VERSION 5.7 ;
  NOWIREEXTENSIONATPIN ON ;
  DIVIDERCHAR "/" ;
  BUSBITCHARS "[]" ;
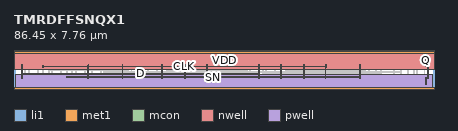
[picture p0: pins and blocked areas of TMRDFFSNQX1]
MACRO TMRDFFSNQX1
  CLASS CORE ;
  FOREIGN TMRDFFSNQX1 ;
  ORIGIN 0.000 0.000 ;
  SIZE 86.450 BY 7.760 ;
  SYMMETRY X Y ;
  SITE unitrh ;
  PIN Q
    DIRECTION OUTPUT ;
    USE SIGNAL ;
    ANTENNADIFFAREA 0.771900 ;
    PORT
      LAYER li1 ;
        RECT 84.770 4.845 84.940 7.200 ;
        RECT 84.770 4.675 85.305 4.845 ;
        RECT 85.135 2.345 85.305 4.675 ;
        RECT 84.765 2.175 85.305 2.345 ;
        RECT 84.765 1.020 84.935 2.175 ;
    END
  END Q
  PIN D
    DIRECTION INPUT ;
    USE SIGNAL ;
    ANTENNAGATEAREA 3.099750 ;
    PORT
      LAYER met1 ;
        RECT 1.485 3.225 1.715 3.255 ;
        RECT 25.905 3.225 26.135 3.255 ;
        RECT 50.325 3.225 50.555 3.255 ;
        RECT 1.455 3.055 50.585 3.225 ;
        RECT 1.485 3.025 1.715 3.055 ;
        RECT 25.905 3.025 26.135 3.055 ;
        RECT 50.325 3.025 50.555 3.055 ;
    END
    PORT
      LAYER li1 ;
        RECT 50.355 2.095 50.525 5.045 ;
      LAYER mcon ;
        RECT 50.355 3.055 50.525 3.225 ;
    END
    PORT
      LAYER li1 ;
        RECT 1.515 2.095 1.685 5.045 ;
      LAYER mcon ;
        RECT 1.515 3.055 1.685 3.225 ;
    END
  END D
  PIN CLK
    DIRECTION INPUT ;
    USE SIGNAL ;
    ANTENNAGATEAREA 6.126300 ;
    PORT
      LAYER met1 ;
        RECT 5.925 4.705 6.155 4.735 ;
        RECT 15.175 4.705 15.405 4.735 ;
        RECT 30.345 4.705 30.575 4.735 ;
        RECT 39.595 4.705 39.825 4.735 ;
        RECT 54.765 4.705 54.995 4.735 ;
        RECT 64.015 4.705 64.245 4.735 ;
        RECT 5.895 4.535 64.275 4.705 ;
        RECT 5.925 4.505 6.155 4.535 ;
        RECT 15.175 4.505 15.405 4.535 ;
        RECT 30.345 4.505 30.575 4.535 ;
        RECT 39.595 4.505 39.825 4.535 ;
        RECT 54.765 4.505 54.995 4.535 ;
        RECT 64.015 4.505 64.245 4.535 ;
    END
    PORT
      LAYER li1 ;
        RECT 15.235 4.890 15.405 5.045 ;
        RECT 15.205 4.715 15.405 4.890 ;
        RECT 15.205 2.095 15.375 4.715 ;
      LAYER mcon ;
        RECT 15.205 4.535 15.375 4.705 ;
    END
    PORT
      LAYER li1 ;
        RECT 30.375 2.095 30.545 5.045 ;
      LAYER mcon ;
        RECT 30.375 4.535 30.545 4.705 ;
    END
    PORT
      LAYER li1 ;
        RECT 39.655 4.890 39.825 5.045 ;
        RECT 39.625 4.715 39.825 4.890 ;
        RECT 39.625 2.095 39.795 4.715 ;
      LAYER mcon ;
        RECT 39.625 4.535 39.795 4.705 ;
    END
    PORT
      LAYER li1 ;
        RECT 54.795 2.095 54.965 5.045 ;
      LAYER mcon ;
        RECT 54.795 4.535 54.965 4.705 ;
    END
    PORT
      LAYER li1 ;
        RECT 64.075 4.890 64.245 5.045 ;
        RECT 64.045 4.715 64.245 4.890 ;
        RECT 64.045 2.095 64.215 4.715 ;
      LAYER mcon ;
        RECT 64.045 4.535 64.215 4.705 ;
    END
  END CLK
  PIN SN
    DIRECTION INPUT ;
    USE SIGNAL ;
    ANTENNAGATEAREA 6.089100 ;
    PORT
      LAYER met1 ;
        RECT 10.735 2.485 10.965 2.515 ;
        RECT 22.205 2.485 22.435 2.515 ;
        RECT 35.155 2.485 35.385 2.515 ;
        RECT 46.625 2.485 46.855 2.515 ;
        RECT 59.575 2.485 59.805 2.515 ;
        RECT 71.045 2.485 71.275 2.515 ;
        RECT 10.705 2.315 71.305 2.485 ;
        RECT 10.735 2.285 10.965 2.315 ;
        RECT 22.205 2.285 22.435 2.315 ;
        RECT 35.155 2.285 35.385 2.315 ;
        RECT 46.625 2.285 46.855 2.315 ;
        RECT 59.575 2.285 59.805 2.315 ;
        RECT 71.045 2.285 71.275 2.315 ;
    END
    PORT
      LAYER li1 ;
        RECT 22.235 2.095 22.405 5.045 ;
      LAYER mcon ;
        RECT 22.235 2.315 22.405 2.485 ;
    END
    PORT
      LAYER li1 ;
        RECT 35.185 2.095 35.355 5.045 ;
      LAYER mcon ;
        RECT 35.185 2.315 35.355 2.485 ;
    END
    PORT
      LAYER li1 ;
        RECT 59.605 2.095 59.775 5.045 ;
      LAYER mcon ;
        RECT 59.605 2.315 59.775 2.485 ;
    END
    PORT
      LAYER li1 ;
        RECT 71.075 2.095 71.245 5.045 ;
      LAYER mcon ;
        RECT 71.075 2.315 71.245 2.485 ;
    END
  END SN
  PIN VDD
    DIRECTION INOUT ;
    USE POWER ;
    SHAPE ABUTMENT ;
    PORT
      LAYER nwell ;
        RECT 0.000 4.110 86.450 7.940 ;
      LAYER met1 ;
        RECT 0.000 7.410 86.450 7.760 ;
    END
  END VDD
  PIN GND
    DIRECTION INOUT ;
    USE GROUND ;
    SHAPE ABUTMENT ;
    PORT
      LAYER pwell ;
        RECT 0.320 0.000 86.130 2.900 ;
      LAYER met1 ;
        RECT 0.000 0.000 86.450 0.350 ;
    END
  END GND
  OBS
      LAYER li1 ;
        RECT 0.000 7.410 86.450 7.760 ;
        RECT 0.320 4.290 0.660 7.410 ;
        RECT 1.195 5.315 1.365 7.410 ;
        RECT 1.635 5.465 1.805 7.200 ;
        RECT 2.075 5.735 2.245 7.410 ;
        RECT 2.515 5.465 2.685 7.200 ;
        RECT 2.955 5.735 3.125 7.410 ;
        RECT 1.635 5.295 3.165 5.465 ;
        RECT 2.285 4.890 2.455 5.045 ;
        RECT 2.255 4.715 2.455 4.890 ;
        RECT 0.320 0.350 0.660 2.900 ;
        RECT 2.255 2.095 2.425 4.715 ;
        RECT 1.100 1.845 1.270 1.925 ;
        RECT 2.070 1.845 2.240 1.925 ;
        RECT 2.995 1.920 3.165 5.295 ;
        RECT 3.650 4.290 3.990 7.410 ;
        RECT 4.825 5.395 4.995 7.410 ;
        RECT 5.265 5.420 5.435 7.200 ;
        RECT 5.705 5.735 5.875 7.410 ;
        RECT 6.145 5.420 6.315 7.200 ;
        RECT 6.585 5.735 6.755 7.410 ;
        RECT 7.025 5.420 7.195 7.200 ;
        RECT 7.465 5.735 7.635 7.410 ;
        RECT 5.265 5.250 7.975 5.420 ;
        RECT 1.100 1.675 2.240 1.845 ;
        RECT 1.100 0.545 1.270 1.675 ;
        RECT 1.585 0.350 1.755 1.300 ;
        RECT 2.070 0.795 2.240 1.675 ;
        RECT 2.555 1.750 3.165 1.920 ;
        RECT 2.555 1.015 2.725 1.750 ;
        RECT 3.040 0.795 3.210 1.565 ;
        RECT 2.070 0.625 3.210 0.795 ;
        RECT 2.070 0.545 2.240 0.625 ;
        RECT 3.040 0.545 3.210 0.625 ;
        RECT 3.650 0.350 3.990 2.900 ;
        RECT 4.845 2.095 5.015 5.045 ;
        RECT 5.955 2.095 6.125 5.045 ;
        RECT 7.065 2.095 7.235 5.045 ;
        RECT 7.805 4.415 7.975 5.250 ;
        RECT 7.800 4.085 7.975 4.415 ;
        RECT 8.460 4.290 8.800 7.410 ;
        RECT 9.635 5.395 9.805 7.410 ;
        RECT 10.075 5.420 10.245 7.200 ;
        RECT 10.515 5.735 10.685 7.410 ;
        RECT 10.955 5.420 11.125 7.200 ;
        RECT 11.395 5.735 11.565 7.410 ;
        RECT 11.835 5.420 12.005 7.200 ;
        RECT 12.275 5.735 12.445 7.410 ;
        RECT 10.075 5.250 12.785 5.420 ;
        RECT 4.325 1.855 4.495 1.935 ;
        RECT 5.295 1.855 5.465 1.935 ;
        RECT 6.265 1.855 6.435 1.935 ;
        RECT 4.325 1.685 6.435 1.855 ;
        RECT 4.325 0.555 4.495 1.685 ;
        RECT 4.810 0.350 4.980 1.310 ;
        RECT 5.295 0.805 5.465 1.685 ;
        RECT 6.265 1.605 6.435 1.685 ;
        RECT 5.785 1.260 5.955 1.340 ;
        RECT 6.835 1.260 7.005 1.935 ;
        RECT 7.805 1.930 7.975 4.085 ;
        RECT 5.785 1.090 7.005 1.260 ;
        RECT 5.785 1.010 5.955 1.090 ;
        RECT 6.265 0.805 6.435 0.885 ;
        RECT 5.295 0.635 6.435 0.805 ;
        RECT 5.295 0.555 5.465 0.635 ;
        RECT 6.265 0.555 6.435 0.635 ;
        RECT 6.835 0.805 7.005 1.090 ;
        RECT 7.320 1.760 7.975 1.930 ;
        RECT 7.320 1.025 7.490 1.760 ;
        RECT 7.805 0.805 7.975 1.575 ;
        RECT 6.835 0.635 7.975 0.805 ;
        RECT 6.835 0.555 7.005 0.635 ;
        RECT 7.805 0.555 7.975 0.635 ;
        RECT 8.460 0.350 8.800 2.900 ;
        RECT 9.655 2.095 9.825 5.045 ;
        RECT 10.765 2.095 10.935 5.045 ;
        RECT 11.875 2.095 12.045 5.045 ;
        RECT 9.135 1.855 9.305 1.935 ;
        RECT 10.105 1.855 10.275 1.935 ;
        RECT 11.075 1.855 11.245 1.935 ;
        RECT 9.135 1.685 11.245 1.855 ;
        RECT 9.135 0.555 9.305 1.685 ;
        RECT 9.620 0.350 9.790 1.310 ;
        RECT 10.105 0.805 10.275 1.685 ;
        RECT 11.075 1.605 11.245 1.685 ;
        RECT 10.595 1.260 10.765 1.340 ;
        RECT 11.645 1.260 11.815 1.935 ;
        RECT 12.615 1.930 12.785 5.250 ;
        RECT 13.270 4.290 13.610 7.410 ;
        RECT 14.145 5.315 14.315 7.410 ;
        RECT 14.585 5.465 14.755 7.200 ;
        RECT 15.025 5.735 15.195 7.410 ;
        RECT 15.465 5.465 15.635 7.200 ;
        RECT 15.905 5.735 16.075 7.410 ;
        RECT 14.585 5.295 16.115 5.465 ;
        RECT 10.595 1.090 11.815 1.260 ;
        RECT 10.595 1.010 10.765 1.090 ;
        RECT 11.075 0.805 11.245 0.885 ;
        RECT 10.105 0.635 11.245 0.805 ;
        RECT 10.105 0.555 10.275 0.635 ;
        RECT 11.075 0.555 11.245 0.635 ;
        RECT 11.645 0.805 11.815 1.090 ;
        RECT 12.130 1.760 12.785 1.930 ;
        RECT 12.130 1.025 12.300 1.760 ;
        RECT 12.615 0.805 12.785 1.575 ;
        RECT 11.645 0.635 12.785 0.805 ;
        RECT 11.645 0.555 11.815 0.635 ;
        RECT 12.615 0.555 12.785 0.635 ;
        RECT 13.270 0.350 13.610 2.900 ;
        RECT 14.465 2.095 14.635 5.045 ;
        RECT 14.050 1.845 14.220 1.925 ;
        RECT 15.020 1.845 15.190 1.925 ;
        RECT 15.945 1.920 16.115 5.295 ;
        RECT 16.600 4.290 16.940 7.410 ;
        RECT 17.475 5.315 17.645 7.410 ;
        RECT 17.915 5.465 18.085 7.200 ;
        RECT 18.355 5.735 18.525 7.410 ;
        RECT 18.795 5.465 18.965 7.200 ;
        RECT 19.235 5.735 19.405 7.410 ;
        RECT 17.915 5.295 19.445 5.465 ;
        RECT 14.050 1.675 15.190 1.845 ;
        RECT 14.050 0.545 14.220 1.675 ;
        RECT 14.535 0.350 14.705 1.300 ;
        RECT 15.020 0.795 15.190 1.675 ;
        RECT 15.505 1.750 16.115 1.920 ;
        RECT 15.505 1.015 15.675 1.750 ;
        RECT 15.990 0.795 16.160 1.565 ;
        RECT 15.020 0.625 16.160 0.795 ;
        RECT 15.020 0.545 15.190 0.625 ;
        RECT 15.990 0.545 16.160 0.625 ;
        RECT 16.600 0.350 16.940 2.900 ;
        RECT 17.795 2.095 17.965 5.045 ;
        RECT 18.565 4.890 18.735 5.045 ;
        RECT 18.535 4.715 18.735 4.890 ;
        RECT 18.535 2.095 18.705 4.715 ;
        RECT 17.380 1.845 17.550 1.925 ;
        RECT 18.350 1.845 18.520 1.925 ;
        RECT 19.275 1.920 19.445 5.295 ;
        RECT 19.930 4.290 20.270 7.410 ;
        RECT 21.105 5.395 21.275 7.410 ;
        RECT 21.545 5.420 21.715 7.200 ;
        RECT 21.985 5.735 22.155 7.410 ;
        RECT 22.425 5.420 22.595 7.200 ;
        RECT 22.865 5.735 23.035 7.410 ;
        RECT 23.305 5.420 23.475 7.200 ;
        RECT 23.745 5.735 23.915 7.410 ;
        RECT 21.545 5.250 24.255 5.420 ;
        RECT 17.380 1.675 18.520 1.845 ;
        RECT 17.380 0.545 17.550 1.675 ;
        RECT 17.865 0.350 18.035 1.300 ;
        RECT 18.350 0.795 18.520 1.675 ;
        RECT 18.835 1.750 19.445 1.920 ;
        RECT 18.835 1.015 19.005 1.750 ;
        RECT 19.320 0.795 19.490 1.565 ;
        RECT 18.350 0.625 19.490 0.795 ;
        RECT 18.350 0.545 18.520 0.625 ;
        RECT 19.320 0.545 19.490 0.625 ;
        RECT 19.930 0.350 20.270 2.900 ;
        RECT 21.125 2.095 21.295 5.045 ;
        RECT 23.345 2.095 23.515 5.045 ;
        RECT 20.605 1.855 20.775 1.935 ;
        RECT 21.575 1.855 21.745 1.935 ;
        RECT 22.545 1.855 22.715 1.935 ;
        RECT 20.605 1.685 22.715 1.855 ;
        RECT 20.605 0.555 20.775 1.685 ;
        RECT 21.090 0.350 21.260 1.310 ;
        RECT 21.575 0.805 21.745 1.685 ;
        RECT 22.545 1.605 22.715 1.685 ;
        RECT 22.065 1.260 22.235 1.340 ;
        RECT 23.115 1.260 23.285 1.935 ;
        RECT 24.085 1.930 24.255 5.250 ;
        RECT 24.740 4.290 25.080 7.410 ;
        RECT 25.615 5.315 25.785 7.410 ;
        RECT 26.055 5.465 26.225 7.200 ;
        RECT 26.495 5.735 26.665 7.410 ;
        RECT 26.935 5.465 27.105 7.200 ;
        RECT 27.375 5.735 27.545 7.410 ;
        RECT 26.055 5.295 27.585 5.465 ;
        RECT 22.065 1.090 23.285 1.260 ;
        RECT 22.065 1.010 22.235 1.090 ;
        RECT 22.545 0.805 22.715 0.885 ;
        RECT 21.575 0.635 22.715 0.805 ;
        RECT 21.575 0.555 21.745 0.635 ;
        RECT 22.545 0.555 22.715 0.635 ;
        RECT 23.115 0.805 23.285 1.090 ;
        RECT 23.600 1.760 24.255 1.930 ;
        RECT 23.600 1.025 23.770 1.760 ;
        RECT 24.085 0.805 24.255 1.575 ;
        RECT 23.115 0.635 24.255 0.805 ;
        RECT 23.115 0.555 23.285 0.635 ;
        RECT 24.085 0.555 24.255 0.635 ;
        RECT 24.740 0.350 25.080 2.900 ;
        RECT 25.935 2.095 26.105 5.045 ;
        RECT 26.705 4.890 26.875 5.045 ;
        RECT 26.675 4.715 26.875 4.890 ;
        RECT 26.675 2.095 26.845 4.715 ;
        RECT 25.520 1.845 25.690 1.925 ;
        RECT 26.490 1.845 26.660 1.925 ;
        RECT 27.415 1.920 27.585 5.295 ;
        RECT 28.070 4.290 28.410 7.410 ;
        RECT 29.245 5.395 29.415 7.410 ;
        RECT 29.685 5.420 29.855 7.200 ;
        RECT 30.125 5.735 30.295 7.410 ;
        RECT 30.565 5.420 30.735 7.200 ;
        RECT 31.005 5.735 31.175 7.410 ;
        RECT 31.445 5.420 31.615 7.200 ;
        RECT 31.885 5.735 32.055 7.410 ;
        RECT 29.685 5.250 32.395 5.420 ;
        RECT 25.520 1.675 26.660 1.845 ;
        RECT 25.520 0.545 25.690 1.675 ;
        RECT 26.005 0.350 26.175 1.300 ;
        RECT 26.490 0.795 26.660 1.675 ;
        RECT 26.975 1.750 27.585 1.920 ;
        RECT 26.975 1.015 27.145 1.750 ;
        RECT 27.460 0.795 27.630 1.565 ;
        RECT 26.490 0.625 27.630 0.795 ;
        RECT 26.490 0.545 26.660 0.625 ;
        RECT 27.460 0.545 27.630 0.625 ;
        RECT 28.070 0.350 28.410 2.900 ;
        RECT 29.265 2.095 29.435 5.045 ;
        RECT 31.485 2.095 31.655 5.045 ;
        RECT 32.225 4.415 32.395 5.250 ;
        RECT 32.220 4.085 32.395 4.415 ;
        RECT 32.880 4.290 33.220 7.410 ;
        RECT 34.055 5.395 34.225 7.410 ;
        RECT 34.495 5.420 34.665 7.200 ;
        RECT 34.935 5.735 35.105 7.410 ;
        RECT 35.375 5.420 35.545 7.200 ;
        RECT 35.815 5.735 35.985 7.410 ;
        RECT 36.255 5.420 36.425 7.200 ;
        RECT 36.695 5.735 36.865 7.410 ;
        RECT 34.495 5.250 37.205 5.420 ;
        RECT 28.745 1.855 28.915 1.935 ;
        RECT 29.715 1.855 29.885 1.935 ;
        RECT 30.685 1.855 30.855 1.935 ;
        RECT 28.745 1.685 30.855 1.855 ;
        RECT 28.745 0.555 28.915 1.685 ;
        RECT 29.230 0.350 29.400 1.310 ;
        RECT 29.715 0.805 29.885 1.685 ;
        RECT 30.685 1.605 30.855 1.685 ;
        RECT 30.205 1.260 30.375 1.340 ;
        RECT 31.255 1.260 31.425 1.935 ;
        RECT 32.225 1.930 32.395 4.085 ;
        RECT 30.205 1.090 31.425 1.260 ;
        RECT 30.205 1.010 30.375 1.090 ;
        RECT 30.685 0.805 30.855 0.885 ;
        RECT 29.715 0.635 30.855 0.805 ;
        RECT 29.715 0.555 29.885 0.635 ;
        RECT 30.685 0.555 30.855 0.635 ;
        RECT 31.255 0.805 31.425 1.090 ;
        RECT 31.740 1.760 32.395 1.930 ;
        RECT 31.740 1.025 31.910 1.760 ;
        RECT 32.225 0.805 32.395 1.575 ;
        RECT 31.255 0.635 32.395 0.805 ;
        RECT 31.255 0.555 31.425 0.635 ;
        RECT 32.225 0.555 32.395 0.635 ;
        RECT 32.880 0.350 33.220 2.900 ;
        RECT 34.075 2.095 34.245 5.045 ;
        RECT 36.295 2.095 36.465 5.045 ;
        RECT 33.555 1.855 33.725 1.935 ;
        RECT 34.525 1.855 34.695 1.935 ;
        RECT 35.495 1.855 35.665 1.935 ;
        RECT 33.555 1.685 35.665 1.855 ;
        RECT 33.555 0.555 33.725 1.685 ;
        RECT 34.040 0.350 34.210 1.310 ;
        RECT 34.525 0.805 34.695 1.685 ;
        RECT 35.495 1.605 35.665 1.685 ;
        RECT 35.015 1.260 35.185 1.340 ;
        RECT 36.065 1.260 36.235 1.935 ;
        RECT 37.035 1.930 37.205 5.250 ;
        RECT 37.690 4.290 38.030 7.410 ;
        RECT 38.565 5.315 38.735 7.410 ;
        RECT 39.005 5.465 39.175 7.200 ;
        RECT 39.445 5.735 39.615 7.410 ;
        RECT 39.885 5.465 40.055 7.200 ;
        RECT 40.325 5.735 40.495 7.410 ;
        RECT 39.005 5.295 40.535 5.465 ;
        RECT 35.015 1.090 36.235 1.260 ;
        RECT 35.015 1.010 35.185 1.090 ;
        RECT 35.495 0.805 35.665 0.885 ;
        RECT 34.525 0.635 35.665 0.805 ;
        RECT 34.525 0.555 34.695 0.635 ;
        RECT 35.495 0.555 35.665 0.635 ;
        RECT 36.065 0.805 36.235 1.090 ;
        RECT 36.550 1.760 37.205 1.930 ;
        RECT 36.550 1.025 36.720 1.760 ;
        RECT 37.035 0.805 37.205 1.575 ;
        RECT 36.065 0.635 37.205 0.805 ;
        RECT 36.065 0.555 36.235 0.635 ;
        RECT 37.035 0.555 37.205 0.635 ;
        RECT 37.690 0.350 38.030 2.900 ;
        RECT 38.885 2.095 39.055 5.045 ;
        RECT 38.470 1.845 38.640 1.925 ;
        RECT 39.440 1.845 39.610 1.925 ;
        RECT 40.365 1.920 40.535 5.295 ;
        RECT 41.020 4.290 41.360 7.410 ;
        RECT 41.895 5.315 42.065 7.410 ;
        RECT 42.335 5.465 42.505 7.200 ;
        RECT 42.775 5.735 42.945 7.410 ;
        RECT 43.215 5.465 43.385 7.200 ;
        RECT 43.655 5.735 43.825 7.410 ;
        RECT 42.335 5.295 43.865 5.465 ;
        RECT 38.470 1.675 39.610 1.845 ;
        RECT 38.470 0.545 38.640 1.675 ;
        RECT 38.955 0.350 39.125 1.300 ;
        RECT 39.440 0.795 39.610 1.675 ;
        RECT 39.925 1.750 40.535 1.920 ;
        RECT 39.925 1.015 40.095 1.750 ;
        RECT 40.410 0.795 40.580 1.565 ;
        RECT 39.440 0.625 40.580 0.795 ;
        RECT 39.440 0.545 39.610 0.625 ;
        RECT 40.410 0.545 40.580 0.625 ;
        RECT 41.020 0.350 41.360 2.900 ;
        RECT 42.215 2.095 42.385 5.045 ;
        RECT 42.985 4.890 43.155 5.045 ;
        RECT 42.955 4.715 43.155 4.890 ;
        RECT 42.955 2.095 43.125 4.715 ;
        RECT 41.800 1.845 41.970 1.925 ;
        RECT 42.770 1.845 42.940 1.925 ;
        RECT 43.695 1.920 43.865 5.295 ;
        RECT 44.350 4.290 44.690 7.410 ;
        RECT 45.525 5.395 45.695 7.410 ;
        RECT 45.965 5.420 46.135 7.200 ;
        RECT 46.405 5.735 46.575 7.410 ;
        RECT 46.845 5.420 47.015 7.200 ;
        RECT 47.285 5.735 47.455 7.410 ;
        RECT 47.725 5.420 47.895 7.200 ;
        RECT 48.165 5.735 48.335 7.410 ;
        RECT 45.965 5.250 48.675 5.420 ;
        RECT 41.800 1.675 42.940 1.845 ;
        RECT 41.800 0.545 41.970 1.675 ;
        RECT 42.285 0.350 42.455 1.300 ;
        RECT 42.770 0.795 42.940 1.675 ;
        RECT 43.255 1.750 43.865 1.920 ;
        RECT 43.255 1.015 43.425 1.750 ;
        RECT 43.740 0.795 43.910 1.565 ;
        RECT 42.770 0.625 43.910 0.795 ;
        RECT 42.770 0.545 42.940 0.625 ;
        RECT 43.740 0.545 43.910 0.625 ;
        RECT 44.350 0.350 44.690 2.900 ;
        RECT 45.545 2.095 45.715 5.045 ;
        RECT 46.655 2.095 46.825 5.045 ;
        RECT 47.765 2.095 47.935 5.045 ;
        RECT 45.025 1.855 45.195 1.935 ;
        RECT 45.995 1.855 46.165 1.935 ;
        RECT 46.965 1.855 47.135 1.935 ;
        RECT 45.025 1.685 47.135 1.855 ;
        RECT 45.025 0.555 45.195 1.685 ;
        RECT 45.510 0.350 45.680 1.310 ;
        RECT 45.995 0.805 46.165 1.685 ;
        RECT 46.965 1.605 47.135 1.685 ;
        RECT 46.485 1.260 46.655 1.340 ;
        RECT 47.535 1.260 47.705 1.935 ;
        RECT 48.505 1.930 48.675 5.250 ;
        RECT 49.160 4.290 49.500 7.410 ;
        RECT 50.035 5.315 50.205 7.410 ;
        RECT 50.475 5.465 50.645 7.200 ;
        RECT 50.915 5.735 51.085 7.410 ;
        RECT 51.355 5.465 51.525 7.200 ;
        RECT 51.795 5.735 51.965 7.410 ;
        RECT 50.475 5.295 52.005 5.465 ;
        RECT 51.125 4.890 51.295 5.045 ;
        RECT 51.095 4.715 51.295 4.890 ;
        RECT 46.485 1.090 47.705 1.260 ;
        RECT 46.485 1.010 46.655 1.090 ;
        RECT 46.965 0.805 47.135 0.885 ;
        RECT 45.995 0.635 47.135 0.805 ;
        RECT 45.995 0.555 46.165 0.635 ;
        RECT 46.965 0.555 47.135 0.635 ;
        RECT 47.535 0.805 47.705 1.090 ;
        RECT 48.020 1.760 48.675 1.930 ;
        RECT 48.020 1.025 48.190 1.760 ;
        RECT 48.505 0.805 48.675 1.575 ;
        RECT 47.535 0.635 48.675 0.805 ;
        RECT 47.535 0.555 47.705 0.635 ;
        RECT 48.505 0.555 48.675 0.635 ;
        RECT 49.160 0.350 49.500 2.900 ;
        RECT 51.095 2.095 51.265 4.715 ;
        RECT 49.940 1.845 50.110 1.925 ;
        RECT 50.910 1.845 51.080 1.925 ;
        RECT 51.835 1.920 52.005 5.295 ;
        RECT 52.490 4.290 52.830 7.410 ;
        RECT 53.665 5.395 53.835 7.410 ;
        RECT 54.105 5.420 54.275 7.200 ;
        RECT 54.545 5.735 54.715 7.410 ;
        RECT 54.985 5.420 55.155 7.200 ;
        RECT 55.425 5.735 55.595 7.410 ;
        RECT 55.865 5.420 56.035 7.200 ;
        RECT 56.305 5.735 56.475 7.410 ;
        RECT 54.105 5.250 56.815 5.420 ;
        RECT 49.940 1.675 51.080 1.845 ;
        RECT 49.940 0.545 50.110 1.675 ;
        RECT 50.425 0.350 50.595 1.300 ;
        RECT 50.910 0.795 51.080 1.675 ;
        RECT 51.395 1.750 52.005 1.920 ;
        RECT 51.395 1.015 51.565 1.750 ;
        RECT 51.880 0.795 52.050 1.565 ;
        RECT 50.910 0.625 52.050 0.795 ;
        RECT 50.910 0.545 51.080 0.625 ;
        RECT 51.880 0.545 52.050 0.625 ;
        RECT 52.490 0.350 52.830 2.900 ;
        RECT 53.685 2.095 53.855 5.045 ;
        RECT 55.905 2.095 56.075 5.045 ;
        RECT 56.645 4.415 56.815 5.250 ;
        RECT 56.640 4.085 56.815 4.415 ;
        RECT 57.300 4.290 57.640 7.410 ;
        RECT 58.475 5.395 58.645 7.410 ;
        RECT 58.915 5.420 59.085 7.200 ;
        RECT 59.355 5.735 59.525 7.410 ;
        RECT 59.795 5.420 59.965 7.200 ;
        RECT 60.235 5.735 60.405 7.410 ;
        RECT 60.675 5.420 60.845 7.200 ;
        RECT 61.115 5.735 61.285 7.410 ;
        RECT 58.915 5.250 61.625 5.420 ;
        RECT 53.165 1.855 53.335 1.935 ;
        RECT 54.135 1.855 54.305 1.935 ;
        RECT 55.105 1.855 55.275 1.935 ;
        RECT 53.165 1.685 55.275 1.855 ;
        RECT 53.165 0.555 53.335 1.685 ;
        RECT 53.650 0.350 53.820 1.310 ;
        RECT 54.135 0.805 54.305 1.685 ;
        RECT 55.105 1.605 55.275 1.685 ;
        RECT 54.625 1.260 54.795 1.340 ;
        RECT 55.675 1.260 55.845 1.935 ;
        RECT 56.645 1.930 56.815 4.085 ;
        RECT 54.625 1.090 55.845 1.260 ;
        RECT 54.625 1.010 54.795 1.090 ;
        RECT 55.105 0.805 55.275 0.885 ;
        RECT 54.135 0.635 55.275 0.805 ;
        RECT 54.135 0.555 54.305 0.635 ;
        RECT 55.105 0.555 55.275 0.635 ;
        RECT 55.675 0.805 55.845 1.090 ;
        RECT 56.160 1.760 56.815 1.930 ;
        RECT 56.160 1.025 56.330 1.760 ;
        RECT 56.645 0.805 56.815 1.575 ;
        RECT 55.675 0.635 56.815 0.805 ;
        RECT 55.675 0.555 55.845 0.635 ;
        RECT 56.645 0.555 56.815 0.635 ;
        RECT 57.300 0.350 57.640 2.900 ;
        RECT 58.495 2.095 58.665 5.045 ;
        RECT 60.715 2.095 60.885 5.045 ;
        RECT 57.975 1.855 58.145 1.935 ;
        RECT 58.945 1.855 59.115 1.935 ;
        RECT 59.915 1.855 60.085 1.935 ;
        RECT 57.975 1.685 60.085 1.855 ;
        RECT 57.975 0.555 58.145 1.685 ;
        RECT 58.460 0.350 58.630 1.310 ;
        RECT 58.945 0.805 59.115 1.685 ;
        RECT 59.915 1.605 60.085 1.685 ;
        RECT 59.435 1.260 59.605 1.340 ;
        RECT 60.485 1.260 60.655 1.935 ;
        RECT 61.455 1.930 61.625 5.250 ;
        RECT 62.110 4.290 62.450 7.410 ;
        RECT 62.985 5.315 63.155 7.410 ;
        RECT 63.425 5.465 63.595 7.200 ;
        RECT 63.865 5.735 64.035 7.410 ;
        RECT 64.305 5.465 64.475 7.200 ;
        RECT 64.745 5.735 64.915 7.410 ;
        RECT 63.425 5.295 64.955 5.465 ;
        RECT 59.435 1.090 60.655 1.260 ;
        RECT 59.435 1.010 59.605 1.090 ;
        RECT 59.915 0.805 60.085 0.885 ;
        RECT 58.945 0.635 60.085 0.805 ;
        RECT 58.945 0.555 59.115 0.635 ;
        RECT 59.915 0.555 60.085 0.635 ;
        RECT 60.485 0.805 60.655 1.090 ;
        RECT 60.970 1.760 61.625 1.930 ;
        RECT 60.970 1.025 61.140 1.760 ;
        RECT 61.455 0.805 61.625 1.575 ;
        RECT 60.485 0.635 61.625 0.805 ;
        RECT 60.485 0.555 60.655 0.635 ;
        RECT 61.455 0.555 61.625 0.635 ;
        RECT 62.110 0.350 62.450 2.900 ;
        RECT 63.305 2.095 63.475 5.045 ;
        RECT 62.890 1.845 63.060 1.925 ;
        RECT 63.860 1.845 64.030 1.925 ;
        RECT 64.785 1.920 64.955 5.295 ;
        RECT 65.440 4.290 65.780 7.410 ;
        RECT 66.315 5.315 66.485 7.410 ;
        RECT 66.755 5.465 66.925 7.200 ;
        RECT 67.195 5.735 67.365 7.410 ;
        RECT 67.635 5.465 67.805 7.200 ;
        RECT 68.075 5.735 68.245 7.410 ;
        RECT 66.755 5.295 68.285 5.465 ;
        RECT 62.890 1.675 64.030 1.845 ;
        RECT 62.890 0.545 63.060 1.675 ;
        RECT 63.375 0.350 63.545 1.300 ;
        RECT 63.860 0.795 64.030 1.675 ;
        RECT 64.345 1.750 64.955 1.920 ;
        RECT 64.345 1.015 64.515 1.750 ;
        RECT 64.830 0.795 65.000 1.565 ;
        RECT 63.860 0.625 65.000 0.795 ;
        RECT 63.860 0.545 64.030 0.625 ;
        RECT 64.830 0.545 65.000 0.625 ;
        RECT 65.440 0.350 65.780 2.900 ;
        RECT 66.635 2.095 66.805 5.045 ;
        RECT 67.405 4.890 67.575 5.045 ;
        RECT 67.375 4.715 67.575 4.890 ;
        RECT 67.375 2.095 67.545 4.715 ;
        RECT 66.220 1.845 66.390 1.925 ;
        RECT 67.190 1.845 67.360 1.925 ;
        RECT 68.115 1.920 68.285 5.295 ;
        RECT 68.770 4.290 69.110 7.410 ;
        RECT 69.945 5.395 70.115 7.410 ;
        RECT 70.385 5.420 70.555 7.200 ;
        RECT 70.825 5.735 70.995 7.410 ;
        RECT 71.265 5.420 71.435 7.200 ;
        RECT 71.705 5.735 71.875 7.410 ;
        RECT 72.145 5.420 72.315 7.200 ;
        RECT 72.585 5.735 72.755 7.410 ;
        RECT 70.385 5.250 73.095 5.420 ;
        RECT 66.220 1.675 67.360 1.845 ;
        RECT 66.220 0.545 66.390 1.675 ;
        RECT 66.705 0.350 66.875 1.300 ;
        RECT 67.190 0.795 67.360 1.675 ;
        RECT 67.675 1.750 68.285 1.920 ;
        RECT 67.675 1.015 67.845 1.750 ;
        RECT 68.160 0.795 68.330 1.565 ;
        RECT 67.190 0.625 68.330 0.795 ;
        RECT 67.190 0.545 67.360 0.625 ;
        RECT 68.160 0.545 68.330 0.625 ;
        RECT 68.770 0.350 69.110 2.900 ;
        RECT 69.965 2.095 70.135 5.155 ;
        RECT 72.185 2.095 72.355 5.045 ;
        RECT 69.445 1.855 69.615 1.935 ;
        RECT 70.415 1.855 70.585 1.935 ;
        RECT 71.385 1.855 71.555 1.935 ;
        RECT 69.445 1.685 71.555 1.855 ;
        RECT 69.445 0.555 69.615 1.685 ;
        RECT 69.930 0.350 70.100 1.310 ;
        RECT 70.415 0.805 70.585 1.685 ;
        RECT 71.385 1.605 71.555 1.685 ;
        RECT 70.905 1.260 71.075 1.340 ;
        RECT 71.955 1.260 72.125 1.935 ;
        RECT 72.925 1.930 73.095 5.250 ;
        RECT 73.580 4.290 73.920 7.410 ;
        RECT 74.455 5.305 74.625 7.410 ;
        RECT 74.895 7.005 75.075 7.175 ;
        RECT 74.895 5.475 75.065 7.005 ;
        RECT 75.335 5.735 75.505 7.410 ;
        RECT 75.775 5.475 75.945 7.175 ;
        RECT 74.895 5.305 75.945 5.475 ;
        RECT 76.215 5.305 76.385 7.410 ;
        RECT 75.775 5.225 75.945 5.305 ;
        RECT 70.905 1.090 72.125 1.260 ;
        RECT 70.905 1.010 71.075 1.090 ;
        RECT 71.385 0.805 71.555 0.885 ;
        RECT 70.415 0.635 71.555 0.805 ;
        RECT 70.415 0.555 70.585 0.635 ;
        RECT 71.385 0.555 71.555 0.635 ;
        RECT 71.955 0.805 72.125 1.090 ;
        RECT 72.440 1.760 73.095 1.930 ;
        RECT 72.440 1.025 72.610 1.760 ;
        RECT 72.925 0.805 73.095 1.575 ;
        RECT 71.955 0.635 73.095 0.805 ;
        RECT 71.955 0.555 72.125 0.635 ;
        RECT 72.925 0.555 73.095 0.635 ;
        RECT 73.580 0.350 73.920 2.900 ;
        RECT 74.405 2.095 74.575 5.050 ;
        RECT 75.555 4.890 75.725 5.050 ;
        RECT 75.515 4.720 75.725 4.890 ;
        RECT 75.515 2.095 75.685 4.720 ;
        RECT 76.910 4.290 77.250 7.410 ;
        RECT 77.775 7.005 79.705 7.175 ;
        RECT 77.775 5.225 77.945 7.005 ;
        RECT 78.215 5.475 78.385 6.745 ;
        RECT 78.655 5.735 78.825 7.005 ;
        RECT 79.095 5.475 79.265 6.745 ;
        RECT 79.535 5.555 79.705 7.005 ;
        RECT 78.215 5.305 79.265 5.475 ;
        RECT 79.095 5.225 79.265 5.305 ;
        RECT 74.360 1.845 74.530 1.925 ;
        RECT 75.330 1.845 75.500 1.925 ;
        RECT 74.360 1.675 75.500 1.845 ;
        RECT 74.360 0.545 74.530 1.675 ;
        RECT 74.845 0.350 75.015 1.300 ;
        RECT 75.330 0.795 75.500 1.675 ;
        RECT 75.815 1.350 75.985 1.525 ;
        RECT 75.810 1.195 75.985 1.350 ;
        RECT 75.810 1.015 75.980 1.195 ;
        RECT 76.300 0.795 76.470 1.925 ;
        RECT 75.330 0.625 76.470 0.795 ;
        RECT 75.330 0.545 75.500 0.625 ;
        RECT 76.300 0.545 76.470 0.625 ;
        RECT 76.910 0.350 77.250 2.900 ;
        RECT 78.105 2.095 78.275 5.050 ;
        RECT 79.585 2.095 79.755 5.050 ;
        RECT 80.240 4.290 80.580 7.410 ;
        RECT 81.115 7.005 83.045 7.175 ;
        RECT 81.115 5.225 81.285 7.005 ;
        RECT 81.555 5.475 81.725 6.745 ;
        RECT 81.995 5.735 82.165 7.005 ;
        RECT 82.435 5.475 82.605 6.745 ;
        RECT 82.875 5.735 83.045 7.005 ;
        RECT 81.555 5.305 83.085 5.475 ;
        RECT 77.690 1.845 77.860 1.925 ;
        RECT 78.660 1.845 78.830 1.925 ;
        RECT 77.690 1.675 78.830 1.845 ;
        RECT 77.690 0.545 77.860 1.675 ;
        RECT 78.175 0.350 78.345 1.300 ;
        RECT 78.660 0.795 78.830 1.675 ;
        RECT 79.145 1.015 79.315 1.525 ;
        RECT 79.630 0.795 79.800 1.925 ;
        RECT 78.660 0.625 79.800 0.795 ;
        RECT 78.660 0.545 78.830 0.625 ;
        RECT 79.630 0.545 79.800 0.625 ;
        RECT 80.240 0.350 80.580 2.900 ;
        RECT 81.065 2.095 81.235 5.050 ;
        RECT 82.175 4.720 82.365 5.050 ;
        RECT 82.175 2.095 82.345 4.720 ;
        RECT 81.020 1.845 81.190 1.925 ;
        RECT 81.990 1.845 82.160 1.925 ;
        RECT 82.915 1.910 83.085 5.305 ;
        RECT 83.570 4.290 83.910 7.410 ;
        RECT 84.330 5.365 84.500 7.410 ;
        RECT 85.210 5.365 85.380 7.410 ;
        RECT 81.020 1.675 82.160 1.845 ;
        RECT 81.020 0.545 81.190 1.675 ;
        RECT 81.505 0.350 81.675 1.300 ;
        RECT 81.990 0.795 82.160 1.675 ;
        RECT 82.475 1.740 83.085 1.910 ;
        RECT 82.475 1.015 82.645 1.740 ;
        RECT 82.960 0.795 83.130 1.570 ;
        RECT 81.990 0.625 83.130 0.795 ;
        RECT 81.990 0.545 82.160 0.625 ;
        RECT 82.960 0.545 83.130 0.625 ;
        RECT 83.570 0.350 83.910 2.900 ;
        RECT 84.395 2.100 84.565 5.045 ;
        RECT 85.790 4.290 86.130 7.410 ;
        RECT 84.285 0.800 84.455 1.930 ;
        RECT 85.255 0.800 85.425 1.930 ;
        RECT 84.285 0.630 85.425 0.800 ;
        RECT 84.285 0.350 84.455 0.630 ;
        RECT 84.770 0.350 84.940 0.630 ;
        RECT 85.255 0.350 85.425 0.630 ;
        RECT 85.790 0.350 86.130 2.900 ;
        RECT 0.000 0.000 86.450 0.350 ;
      LAYER mcon ;
        RECT 0.775 7.495 0.945 7.665 ;
        RECT 1.145 7.495 1.315 7.665 ;
        RECT 1.515 7.495 1.685 7.665 ;
        RECT 1.885 7.495 2.055 7.665 ;
        RECT 2.255 7.495 2.425 7.665 ;
        RECT 2.625 7.495 2.795 7.665 ;
        RECT 2.995 7.495 3.165 7.665 ;
        RECT 3.365 7.495 3.535 7.665 ;
        RECT 4.105 7.495 4.275 7.665 ;
        RECT 4.475 7.495 4.645 7.665 ;
        RECT 4.845 7.495 5.015 7.665 ;
        RECT 5.215 7.495 5.385 7.665 ;
        RECT 5.585 7.495 5.755 7.665 ;
        RECT 5.955 7.495 6.125 7.665 ;
        RECT 6.325 7.495 6.495 7.665 ;
        RECT 6.695 7.495 6.865 7.665 ;
        RECT 7.065 7.495 7.235 7.665 ;
        RECT 7.435 7.495 7.605 7.665 ;
        RECT 7.805 7.495 7.975 7.665 ;
        RECT 8.175 7.495 8.345 7.665 ;
        RECT 8.915 7.495 9.085 7.665 ;
        RECT 9.285 7.495 9.455 7.665 ;
        RECT 9.655 7.495 9.825 7.665 ;
        RECT 10.025 7.495 10.195 7.665 ;
        RECT 10.395 7.495 10.565 7.665 ;
        RECT 10.765 7.495 10.935 7.665 ;
        RECT 11.135 7.495 11.305 7.665 ;
        RECT 11.505 7.495 11.675 7.665 ;
        RECT 11.875 7.495 12.045 7.665 ;
        RECT 12.245 7.495 12.415 7.665 ;
        RECT 12.615 7.495 12.785 7.665 ;
        RECT 12.985 7.495 13.155 7.665 ;
        RECT 13.725 7.495 13.895 7.665 ;
        RECT 14.095 7.495 14.265 7.665 ;
        RECT 14.465 7.495 14.635 7.665 ;
        RECT 14.835 7.495 15.005 7.665 ;
        RECT 15.205 7.495 15.375 7.665 ;
        RECT 15.575 7.495 15.745 7.665 ;
        RECT 15.945 7.495 16.115 7.665 ;
        RECT 16.315 7.495 16.485 7.665 ;
        RECT 17.055 7.495 17.225 7.665 ;
        RECT 17.425 7.495 17.595 7.665 ;
        RECT 17.795 7.495 17.965 7.665 ;
        RECT 18.165 7.495 18.335 7.665 ;
        RECT 18.535 7.495 18.705 7.665 ;
        RECT 18.905 7.495 19.075 7.665 ;
        RECT 19.275 7.495 19.445 7.665 ;
        RECT 19.645 7.495 19.815 7.665 ;
        RECT 20.385 7.495 20.555 7.665 ;
        RECT 20.755 7.495 20.925 7.665 ;
        RECT 21.125 7.495 21.295 7.665 ;
        RECT 21.495 7.495 21.665 7.665 ;
        RECT 21.865 7.495 22.035 7.665 ;
        RECT 22.235 7.495 22.405 7.665 ;
        RECT 22.605 7.495 22.775 7.665 ;
        RECT 22.975 7.495 23.145 7.665 ;
        RECT 23.345 7.495 23.515 7.665 ;
        RECT 23.715 7.495 23.885 7.665 ;
        RECT 24.085 7.495 24.255 7.665 ;
        RECT 24.455 7.495 24.625 7.665 ;
        RECT 25.195 7.495 25.365 7.665 ;
        RECT 25.565 7.495 25.735 7.665 ;
        RECT 25.935 7.495 26.105 7.665 ;
        RECT 26.305 7.495 26.475 7.665 ;
        RECT 26.675 7.495 26.845 7.665 ;
        RECT 27.045 7.495 27.215 7.665 ;
        RECT 27.415 7.495 27.585 7.665 ;
        RECT 27.785 7.495 27.955 7.665 ;
        RECT 28.525 7.495 28.695 7.665 ;
        RECT 28.895 7.495 29.065 7.665 ;
        RECT 29.265 7.495 29.435 7.665 ;
        RECT 29.635 7.495 29.805 7.665 ;
        RECT 30.005 7.495 30.175 7.665 ;
        RECT 30.375 7.495 30.545 7.665 ;
        RECT 30.745 7.495 30.915 7.665 ;
        RECT 31.115 7.495 31.285 7.665 ;
        RECT 31.485 7.495 31.655 7.665 ;
        RECT 31.855 7.495 32.025 7.665 ;
        RECT 32.225 7.495 32.395 7.665 ;
        RECT 32.595 7.495 32.765 7.665 ;
        RECT 33.335 7.495 33.505 7.665 ;
        RECT 33.705 7.495 33.875 7.665 ;
        RECT 34.075 7.495 34.245 7.665 ;
        RECT 34.445 7.495 34.615 7.665 ;
        RECT 34.815 7.495 34.985 7.665 ;
        RECT 35.185 7.495 35.355 7.665 ;
        RECT 35.555 7.495 35.725 7.665 ;
        RECT 35.925 7.495 36.095 7.665 ;
        RECT 36.295 7.495 36.465 7.665 ;
        RECT 36.665 7.495 36.835 7.665 ;
        RECT 37.035 7.495 37.205 7.665 ;
        RECT 37.405 7.495 37.575 7.665 ;
        RECT 38.145 7.495 38.315 7.665 ;
        RECT 38.515 7.495 38.685 7.665 ;
        RECT 38.885 7.495 39.055 7.665 ;
        RECT 39.255 7.495 39.425 7.665 ;
        RECT 39.625 7.495 39.795 7.665 ;
        RECT 39.995 7.495 40.165 7.665 ;
        RECT 40.365 7.495 40.535 7.665 ;
        RECT 40.735 7.495 40.905 7.665 ;
        RECT 41.475 7.495 41.645 7.665 ;
        RECT 41.845 7.495 42.015 7.665 ;
        RECT 42.215 7.495 42.385 7.665 ;
        RECT 42.585 7.495 42.755 7.665 ;
        RECT 42.955 7.495 43.125 7.665 ;
        RECT 43.325 7.495 43.495 7.665 ;
        RECT 43.695 7.495 43.865 7.665 ;
        RECT 44.065 7.495 44.235 7.665 ;
        RECT 44.805 7.495 44.975 7.665 ;
        RECT 45.175 7.495 45.345 7.665 ;
        RECT 45.545 7.495 45.715 7.665 ;
        RECT 45.915 7.495 46.085 7.665 ;
        RECT 46.285 7.495 46.455 7.665 ;
        RECT 46.655 7.495 46.825 7.665 ;
        RECT 47.025 7.495 47.195 7.665 ;
        RECT 47.395 7.495 47.565 7.665 ;
        RECT 47.765 7.495 47.935 7.665 ;
        RECT 48.135 7.495 48.305 7.665 ;
        RECT 48.505 7.495 48.675 7.665 ;
        RECT 48.875 7.495 49.045 7.665 ;
        RECT 49.615 7.495 49.785 7.665 ;
        RECT 49.985 7.495 50.155 7.665 ;
        RECT 50.355 7.495 50.525 7.665 ;
        RECT 50.725 7.495 50.895 7.665 ;
        RECT 51.095 7.495 51.265 7.665 ;
        RECT 51.465 7.495 51.635 7.665 ;
        RECT 51.835 7.495 52.005 7.665 ;
        RECT 52.205 7.495 52.375 7.665 ;
        RECT 52.945 7.495 53.115 7.665 ;
        RECT 53.315 7.495 53.485 7.665 ;
        RECT 53.685 7.495 53.855 7.665 ;
        RECT 54.055 7.495 54.225 7.665 ;
        RECT 54.425 7.495 54.595 7.665 ;
        RECT 54.795 7.495 54.965 7.665 ;
        RECT 55.165 7.495 55.335 7.665 ;
        RECT 55.535 7.495 55.705 7.665 ;
        RECT 55.905 7.495 56.075 7.665 ;
        RECT 56.275 7.495 56.445 7.665 ;
        RECT 56.645 7.495 56.815 7.665 ;
        RECT 57.015 7.495 57.185 7.665 ;
        RECT 57.755 7.495 57.925 7.665 ;
        RECT 58.125 7.495 58.295 7.665 ;
        RECT 58.495 7.495 58.665 7.665 ;
        RECT 58.865 7.495 59.035 7.665 ;
        RECT 59.235 7.495 59.405 7.665 ;
        RECT 59.605 7.495 59.775 7.665 ;
        RECT 59.975 7.495 60.145 7.665 ;
        RECT 60.345 7.495 60.515 7.665 ;
        RECT 60.715 7.495 60.885 7.665 ;
        RECT 61.085 7.495 61.255 7.665 ;
        RECT 61.455 7.495 61.625 7.665 ;
        RECT 61.825 7.495 61.995 7.665 ;
        RECT 62.565 7.495 62.735 7.665 ;
        RECT 62.935 7.495 63.105 7.665 ;
        RECT 63.305 7.495 63.475 7.665 ;
        RECT 63.675 7.495 63.845 7.665 ;
        RECT 64.045 7.495 64.215 7.665 ;
        RECT 64.415 7.495 64.585 7.665 ;
        RECT 64.785 7.495 64.955 7.665 ;
        RECT 65.155 7.495 65.325 7.665 ;
        RECT 65.895 7.495 66.065 7.665 ;
        RECT 66.265 7.495 66.435 7.665 ;
        RECT 66.635 7.495 66.805 7.665 ;
        RECT 67.005 7.495 67.175 7.665 ;
        RECT 67.375 7.495 67.545 7.665 ;
        RECT 67.745 7.495 67.915 7.665 ;
        RECT 68.115 7.495 68.285 7.665 ;
        RECT 68.485 7.495 68.655 7.665 ;
        RECT 69.225 7.495 69.395 7.665 ;
        RECT 69.595 7.495 69.765 7.665 ;
        RECT 69.965 7.495 70.135 7.665 ;
        RECT 70.335 7.495 70.505 7.665 ;
        RECT 70.705 7.495 70.875 7.665 ;
        RECT 71.075 7.495 71.245 7.665 ;
        RECT 71.445 7.495 71.615 7.665 ;
        RECT 71.815 7.495 71.985 7.665 ;
        RECT 72.185 7.495 72.355 7.665 ;
        RECT 72.555 7.495 72.725 7.665 ;
        RECT 72.925 7.495 73.095 7.665 ;
        RECT 73.295 7.495 73.465 7.665 ;
        RECT 74.035 7.495 74.205 7.665 ;
        RECT 74.405 7.495 74.575 7.665 ;
        RECT 74.775 7.495 74.945 7.665 ;
        RECT 75.145 7.495 75.315 7.665 ;
        RECT 75.515 7.495 75.685 7.665 ;
        RECT 75.885 7.495 76.055 7.665 ;
        RECT 76.255 7.495 76.425 7.665 ;
        RECT 76.625 7.495 76.795 7.665 ;
        RECT 77.365 7.495 77.535 7.665 ;
        RECT 77.735 7.495 77.905 7.665 ;
        RECT 78.105 7.495 78.275 7.665 ;
        RECT 78.475 7.495 78.645 7.665 ;
        RECT 78.845 7.495 79.015 7.665 ;
        RECT 79.215 7.495 79.385 7.665 ;
        RECT 79.585 7.495 79.755 7.665 ;
        RECT 79.955 7.495 80.125 7.665 ;
        RECT 80.695 7.495 80.865 7.665 ;
        RECT 81.065 7.495 81.235 7.665 ;
        RECT 81.435 7.495 81.605 7.665 ;
        RECT 81.805 7.495 81.975 7.665 ;
        RECT 82.175 7.495 82.345 7.665 ;
        RECT 82.545 7.495 82.715 7.665 ;
        RECT 82.915 7.495 83.085 7.665 ;
        RECT 83.285 7.495 83.455 7.665 ;
        RECT 84.025 7.495 84.195 7.665 ;
        RECT 84.395 7.495 84.565 7.665 ;
        RECT 84.765 7.495 84.935 7.665 ;
        RECT 85.135 7.495 85.305 7.665 ;
        RECT 85.505 7.495 85.675 7.665 ;
        RECT 2.255 4.165 2.425 4.335 ;
        RECT 2.995 2.685 3.165 2.855 ;
        RECT 4.845 2.680 5.015 2.850 ;
        RECT 5.955 4.535 6.125 4.705 ;
        RECT 7.800 4.165 7.970 4.335 ;
        RECT 7.065 3.795 7.235 3.965 ;
        RECT 9.655 2.685 9.825 2.855 ;
        RECT 10.765 2.315 10.935 2.485 ;
        RECT 11.875 3.795 12.045 3.965 ;
        RECT 12.615 2.685 12.785 2.855 ;
        RECT 14.465 2.685 14.635 2.855 ;
        RECT 15.945 3.795 16.115 3.965 ;
        RECT 17.795 4.165 17.965 4.335 ;
        RECT 18.535 3.425 18.705 3.595 ;
        RECT 19.275 4.165 19.445 4.335 ;
        RECT 21.125 4.165 21.295 4.335 ;
        RECT 23.345 3.795 23.515 3.965 ;
        RECT 24.085 3.425 24.255 3.595 ;
        RECT 25.935 3.055 26.105 3.225 ;
        RECT 26.675 4.165 26.845 4.335 ;
        RECT 27.415 2.685 27.585 2.855 ;
        RECT 29.265 2.680 29.435 2.850 ;
        RECT 32.220 4.165 32.390 4.335 ;
        RECT 31.485 3.795 31.655 3.965 ;
        RECT 34.075 2.685 34.245 2.855 ;
        RECT 36.295 3.795 36.465 3.965 ;
        RECT 37.035 2.685 37.205 2.855 ;
        RECT 38.885 2.685 39.055 2.855 ;
        RECT 40.365 3.795 40.535 3.965 ;
        RECT 42.215 4.165 42.385 4.335 ;
        RECT 42.955 4.165 43.125 4.335 ;
        RECT 43.695 2.685 43.865 2.855 ;
        RECT 45.545 2.685 45.715 2.855 ;
        RECT 46.655 2.315 46.825 2.485 ;
        RECT 47.765 3.795 47.935 3.965 ;
        RECT 48.505 4.165 48.675 4.335 ;
        RECT 51.095 4.165 51.265 4.335 ;
        RECT 48.505 2.685 48.675 2.855 ;
        RECT 51.835 2.685 52.005 2.855 ;
        RECT 53.685 2.680 53.855 2.850 ;
        RECT 56.640 4.165 56.810 4.335 ;
        RECT 55.905 3.795 56.075 3.965 ;
        RECT 58.495 2.685 58.665 2.855 ;
        RECT 60.715 3.795 60.885 3.965 ;
        RECT 61.455 2.685 61.625 2.855 ;
        RECT 63.305 2.685 63.475 2.855 ;
        RECT 64.785 3.795 64.955 3.965 ;
        RECT 66.635 4.165 66.805 4.335 ;
        RECT 68.115 4.905 68.285 5.075 ;
        RECT 67.375 4.535 67.545 4.705 ;
        RECT 69.965 4.905 70.135 5.075 ;
        RECT 72.185 3.795 72.355 3.965 ;
        RECT 72.925 4.535 73.095 4.705 ;
        RECT 75.775 5.305 75.945 5.475 ;
        RECT 74.405 4.535 74.575 4.705 ;
        RECT 75.515 4.165 75.685 4.335 ;
        RECT 77.775 5.305 77.945 5.475 ;
        RECT 79.095 5.305 79.265 5.475 ;
        RECT 78.105 4.535 78.275 4.705 ;
        RECT 75.515 3.055 75.685 3.225 ;
        RECT 75.815 1.275 75.985 1.445 ;
        RECT 81.115 5.305 81.285 5.475 ;
        RECT 79.585 3.425 79.755 3.595 ;
        RECT 79.585 2.175 79.755 2.345 ;
        RECT 79.145 1.275 79.315 1.445 ;
        RECT 81.065 2.175 81.235 2.345 ;
        RECT 82.175 4.165 82.345 4.335 ;
        RECT 82.915 4.165 83.085 4.335 ;
        RECT 84.395 4.165 84.565 4.335 ;
        RECT 82.475 1.275 82.645 1.445 ;
        RECT 0.775 0.095 0.945 0.265 ;
        RECT 1.145 0.095 1.315 0.265 ;
        RECT 1.515 0.095 1.685 0.265 ;
        RECT 1.885 0.095 2.055 0.265 ;
        RECT 2.255 0.095 2.425 0.265 ;
        RECT 2.625 0.095 2.795 0.265 ;
        RECT 2.995 0.095 3.165 0.265 ;
        RECT 3.365 0.095 3.535 0.265 ;
        RECT 4.105 0.095 4.275 0.265 ;
        RECT 4.475 0.095 4.645 0.265 ;
        RECT 4.845 0.095 5.015 0.265 ;
        RECT 5.215 0.095 5.385 0.265 ;
        RECT 5.585 0.095 5.755 0.265 ;
        RECT 5.955 0.095 6.125 0.265 ;
        RECT 6.325 0.095 6.495 0.265 ;
        RECT 6.695 0.095 6.865 0.265 ;
        RECT 7.065 0.095 7.235 0.265 ;
        RECT 7.435 0.095 7.605 0.265 ;
        RECT 7.805 0.095 7.975 0.265 ;
        RECT 8.175 0.095 8.345 0.265 ;
        RECT 8.915 0.095 9.085 0.265 ;
        RECT 9.285 0.095 9.455 0.265 ;
        RECT 9.655 0.095 9.825 0.265 ;
        RECT 10.025 0.095 10.195 0.265 ;
        RECT 10.395 0.095 10.565 0.265 ;
        RECT 10.765 0.095 10.935 0.265 ;
        RECT 11.135 0.095 11.305 0.265 ;
        RECT 11.505 0.095 11.675 0.265 ;
        RECT 11.875 0.095 12.045 0.265 ;
        RECT 12.245 0.095 12.415 0.265 ;
        RECT 12.615 0.095 12.785 0.265 ;
        RECT 12.985 0.095 13.155 0.265 ;
        RECT 13.725 0.095 13.895 0.265 ;
        RECT 14.095 0.095 14.265 0.265 ;
        RECT 14.465 0.095 14.635 0.265 ;
        RECT 14.835 0.095 15.005 0.265 ;
        RECT 15.205 0.095 15.375 0.265 ;
        RECT 15.575 0.095 15.745 0.265 ;
        RECT 15.945 0.095 16.115 0.265 ;
        RECT 16.315 0.095 16.485 0.265 ;
        RECT 17.055 0.095 17.225 0.265 ;
        RECT 17.425 0.095 17.595 0.265 ;
        RECT 17.795 0.095 17.965 0.265 ;
        RECT 18.165 0.095 18.335 0.265 ;
        RECT 18.535 0.095 18.705 0.265 ;
        RECT 18.905 0.095 19.075 0.265 ;
        RECT 19.275 0.095 19.445 0.265 ;
        RECT 19.645 0.095 19.815 0.265 ;
        RECT 20.385 0.095 20.555 0.265 ;
        RECT 20.755 0.095 20.925 0.265 ;
        RECT 21.125 0.095 21.295 0.265 ;
        RECT 21.495 0.095 21.665 0.265 ;
        RECT 21.865 0.095 22.035 0.265 ;
        RECT 22.235 0.095 22.405 0.265 ;
        RECT 22.605 0.095 22.775 0.265 ;
        RECT 22.975 0.095 23.145 0.265 ;
        RECT 23.345 0.095 23.515 0.265 ;
        RECT 23.715 0.095 23.885 0.265 ;
        RECT 24.085 0.095 24.255 0.265 ;
        RECT 24.455 0.095 24.625 0.265 ;
        RECT 25.195 0.095 25.365 0.265 ;
        RECT 25.565 0.095 25.735 0.265 ;
        RECT 25.935 0.095 26.105 0.265 ;
        RECT 26.305 0.095 26.475 0.265 ;
        RECT 26.675 0.095 26.845 0.265 ;
        RECT 27.045 0.095 27.215 0.265 ;
        RECT 27.415 0.095 27.585 0.265 ;
        RECT 27.785 0.095 27.955 0.265 ;
        RECT 28.525 0.095 28.695 0.265 ;
        RECT 28.895 0.095 29.065 0.265 ;
        RECT 29.265 0.095 29.435 0.265 ;
        RECT 29.635 0.095 29.805 0.265 ;
        RECT 30.005 0.095 30.175 0.265 ;
        RECT 30.375 0.095 30.545 0.265 ;
        RECT 30.745 0.095 30.915 0.265 ;
        RECT 31.115 0.095 31.285 0.265 ;
        RECT 31.485 0.095 31.655 0.265 ;
        RECT 31.855 0.095 32.025 0.265 ;
        RECT 32.225 0.095 32.395 0.265 ;
        RECT 32.595 0.095 32.765 0.265 ;
        RECT 33.335 0.095 33.505 0.265 ;
        RECT 33.705 0.095 33.875 0.265 ;
        RECT 34.075 0.095 34.245 0.265 ;
        RECT 34.445 0.095 34.615 0.265 ;
        RECT 34.815 0.095 34.985 0.265 ;
        RECT 35.185 0.095 35.355 0.265 ;
        RECT 35.555 0.095 35.725 0.265 ;
        RECT 35.925 0.095 36.095 0.265 ;
        RECT 36.295 0.095 36.465 0.265 ;
        RECT 36.665 0.095 36.835 0.265 ;
        RECT 37.035 0.095 37.205 0.265 ;
        RECT 37.405 0.095 37.575 0.265 ;
        RECT 38.145 0.095 38.315 0.265 ;
        RECT 38.515 0.095 38.685 0.265 ;
        RECT 38.885 0.095 39.055 0.265 ;
        RECT 39.255 0.095 39.425 0.265 ;
        RECT 39.625 0.095 39.795 0.265 ;
        RECT 39.995 0.095 40.165 0.265 ;
        RECT 40.365 0.095 40.535 0.265 ;
        RECT 40.735 0.095 40.905 0.265 ;
        RECT 41.475 0.095 41.645 0.265 ;
        RECT 41.845 0.095 42.015 0.265 ;
        RECT 42.215 0.095 42.385 0.265 ;
        RECT 42.585 0.095 42.755 0.265 ;
        RECT 42.955 0.095 43.125 0.265 ;
        RECT 43.325 0.095 43.495 0.265 ;
        RECT 43.695 0.095 43.865 0.265 ;
        RECT 44.065 0.095 44.235 0.265 ;
        RECT 44.805 0.095 44.975 0.265 ;
        RECT 45.175 0.095 45.345 0.265 ;
        RECT 45.545 0.095 45.715 0.265 ;
        RECT 45.915 0.095 46.085 0.265 ;
        RECT 46.285 0.095 46.455 0.265 ;
        RECT 46.655 0.095 46.825 0.265 ;
        RECT 47.025 0.095 47.195 0.265 ;
        RECT 47.395 0.095 47.565 0.265 ;
        RECT 47.765 0.095 47.935 0.265 ;
        RECT 48.135 0.095 48.305 0.265 ;
        RECT 48.505 0.095 48.675 0.265 ;
        RECT 48.875 0.095 49.045 0.265 ;
        RECT 49.615 0.095 49.785 0.265 ;
        RECT 49.985 0.095 50.155 0.265 ;
        RECT 50.355 0.095 50.525 0.265 ;
        RECT 50.725 0.095 50.895 0.265 ;
        RECT 51.095 0.095 51.265 0.265 ;
        RECT 51.465 0.095 51.635 0.265 ;
        RECT 51.835 0.095 52.005 0.265 ;
        RECT 52.205 0.095 52.375 0.265 ;
        RECT 52.945 0.095 53.115 0.265 ;
        RECT 53.315 0.095 53.485 0.265 ;
        RECT 53.685 0.095 53.855 0.265 ;
        RECT 54.055 0.095 54.225 0.265 ;
        RECT 54.425 0.095 54.595 0.265 ;
        RECT 54.795 0.095 54.965 0.265 ;
        RECT 55.165 0.095 55.335 0.265 ;
        RECT 55.535 0.095 55.705 0.265 ;
        RECT 55.905 0.095 56.075 0.265 ;
        RECT 56.275 0.095 56.445 0.265 ;
        RECT 56.645 0.095 56.815 0.265 ;
        RECT 57.015 0.095 57.185 0.265 ;
        RECT 57.755 0.095 57.925 0.265 ;
        RECT 58.125 0.095 58.295 0.265 ;
        RECT 58.495 0.095 58.665 0.265 ;
        RECT 58.865 0.095 59.035 0.265 ;
        RECT 59.235 0.095 59.405 0.265 ;
        RECT 59.605 0.095 59.775 0.265 ;
        RECT 59.975 0.095 60.145 0.265 ;
        RECT 60.345 0.095 60.515 0.265 ;
        RECT 60.715 0.095 60.885 0.265 ;
        RECT 61.085 0.095 61.255 0.265 ;
        RECT 61.455 0.095 61.625 0.265 ;
        RECT 61.825 0.095 61.995 0.265 ;
        RECT 62.565 0.095 62.735 0.265 ;
        RECT 62.935 0.095 63.105 0.265 ;
        RECT 63.305 0.095 63.475 0.265 ;
        RECT 63.675 0.095 63.845 0.265 ;
        RECT 64.045 0.095 64.215 0.265 ;
        RECT 64.415 0.095 64.585 0.265 ;
        RECT 64.785 0.095 64.955 0.265 ;
        RECT 65.155 0.095 65.325 0.265 ;
        RECT 65.895 0.095 66.065 0.265 ;
        RECT 66.265 0.095 66.435 0.265 ;
        RECT 66.635 0.095 66.805 0.265 ;
        RECT 67.005 0.095 67.175 0.265 ;
        RECT 67.375 0.095 67.545 0.265 ;
        RECT 67.745 0.095 67.915 0.265 ;
        RECT 68.115 0.095 68.285 0.265 ;
        RECT 68.485 0.095 68.655 0.265 ;
        RECT 69.225 0.095 69.395 0.265 ;
        RECT 69.595 0.095 69.765 0.265 ;
        RECT 69.965 0.095 70.135 0.265 ;
        RECT 70.335 0.095 70.505 0.265 ;
        RECT 70.705 0.095 70.875 0.265 ;
        RECT 71.075 0.095 71.245 0.265 ;
        RECT 71.445 0.095 71.615 0.265 ;
        RECT 71.815 0.095 71.985 0.265 ;
        RECT 72.185 0.095 72.355 0.265 ;
        RECT 72.555 0.095 72.725 0.265 ;
        RECT 72.925 0.095 73.095 0.265 ;
        RECT 73.295 0.095 73.465 0.265 ;
        RECT 74.035 0.095 74.205 0.265 ;
        RECT 74.405 0.095 74.575 0.265 ;
        RECT 74.775 0.095 74.945 0.265 ;
        RECT 75.145 0.095 75.315 0.265 ;
        RECT 75.515 0.095 75.685 0.265 ;
        RECT 75.885 0.095 76.055 0.265 ;
        RECT 76.255 0.095 76.425 0.265 ;
        RECT 76.625 0.095 76.795 0.265 ;
        RECT 77.365 0.095 77.535 0.265 ;
        RECT 77.735 0.095 77.905 0.265 ;
        RECT 78.105 0.095 78.275 0.265 ;
        RECT 78.475 0.095 78.645 0.265 ;
        RECT 78.845 0.095 79.015 0.265 ;
        RECT 79.215 0.095 79.385 0.265 ;
        RECT 79.585 0.095 79.755 0.265 ;
        RECT 79.955 0.095 80.125 0.265 ;
        RECT 80.695 0.095 80.865 0.265 ;
        RECT 81.065 0.095 81.235 0.265 ;
        RECT 81.435 0.095 81.605 0.265 ;
        RECT 81.805 0.095 81.975 0.265 ;
        RECT 82.175 0.095 82.345 0.265 ;
        RECT 82.545 0.095 82.715 0.265 ;
        RECT 82.915 0.095 83.085 0.265 ;
        RECT 83.285 0.095 83.455 0.265 ;
        RECT 84.025 0.095 84.195 0.265 ;
        RECT 84.395 0.095 84.565 0.265 ;
        RECT 84.765 0.095 84.935 0.265 ;
        RECT 85.135 0.095 85.305 0.265 ;
        RECT 85.505 0.095 85.675 0.265 ;
      LAYER met1 ;
        RECT 75.745 5.475 75.975 5.505 ;
        RECT 77.745 5.475 77.975 5.505 ;
        RECT 79.065 5.475 79.295 5.505 ;
        RECT 81.085 5.475 81.315 5.505 ;
        RECT 75.715 5.305 78.005 5.475 ;
        RECT 79.035 5.305 81.345 5.475 ;
        RECT 75.745 5.275 75.975 5.305 ;
        RECT 77.745 5.275 77.975 5.305 ;
        RECT 79.065 5.275 79.295 5.305 ;
        RECT 81.085 5.275 81.315 5.305 ;
        RECT 68.085 5.075 68.315 5.105 ;
        RECT 69.935 5.075 70.165 5.105 ;
        RECT 68.055 4.905 70.195 5.075 ;
        RECT 68.085 4.875 68.315 4.905 ;
        RECT 69.935 4.875 70.165 4.905 ;
        RECT 67.345 4.705 67.575 4.735 ;
        RECT 72.895 4.705 73.125 4.735 ;
        RECT 74.375 4.705 74.605 4.735 ;
        RECT 78.075 4.705 78.305 4.735 ;
        RECT 67.315 4.535 78.335 4.705 ;
        RECT 67.345 4.505 67.575 4.535 ;
        RECT 72.895 4.505 73.125 4.535 ;
        RECT 74.375 4.505 74.605 4.535 ;
        RECT 78.075 4.505 78.305 4.535 ;
        RECT 2.225 4.335 2.455 4.365 ;
        RECT 7.770 4.335 8.000 4.365 ;
        RECT 17.765 4.335 17.995 4.365 ;
        RECT 19.245 4.335 19.475 4.365 ;
        RECT 21.095 4.335 21.325 4.365 ;
        RECT 26.645 4.335 26.875 4.365 ;
        RECT 32.190 4.335 32.420 4.365 ;
        RECT 42.185 4.335 42.415 4.365 ;
        RECT 42.925 4.335 43.155 4.365 ;
        RECT 48.475 4.335 48.705 4.365 ;
        RECT 51.065 4.335 51.295 4.365 ;
        RECT 56.610 4.335 56.840 4.365 ;
        RECT 66.605 4.335 66.835 4.365 ;
        RECT 75.485 4.335 75.715 4.365 ;
        RECT 82.145 4.335 82.375 4.365 ;
        RECT 82.885 4.335 83.115 4.365 ;
        RECT 84.365 4.335 84.595 4.365 ;
        RECT 2.195 4.165 18.025 4.335 ;
        RECT 19.215 4.165 21.355 4.335 ;
        RECT 26.615 4.165 42.445 4.335 ;
        RECT 42.895 4.165 48.735 4.335 ;
        RECT 51.035 4.165 66.865 4.335 ;
        RECT 75.455 4.165 82.405 4.335 ;
        RECT 82.855 4.165 84.625 4.335 ;
        RECT 2.225 4.135 2.455 4.165 ;
        RECT 7.770 4.135 8.000 4.165 ;
        RECT 17.765 4.135 17.995 4.165 ;
        RECT 19.245 4.135 19.475 4.165 ;
        RECT 21.095 4.135 21.325 4.165 ;
        RECT 26.645 4.135 26.875 4.165 ;
        RECT 32.190 4.135 32.420 4.165 ;
        RECT 42.185 4.135 42.415 4.165 ;
        RECT 42.925 4.135 43.155 4.165 ;
        RECT 48.475 4.135 48.705 4.165 ;
        RECT 51.065 4.135 51.295 4.165 ;
        RECT 56.610 4.135 56.840 4.165 ;
        RECT 66.605 4.135 66.835 4.165 ;
        RECT 75.485 4.135 75.715 4.165 ;
        RECT 82.145 4.135 82.375 4.165 ;
        RECT 82.885 4.135 83.115 4.165 ;
        RECT 84.365 4.135 84.595 4.165 ;
        RECT 7.035 3.965 7.265 3.995 ;
        RECT 11.845 3.965 12.075 3.995 ;
        RECT 15.915 3.965 16.145 3.995 ;
        RECT 23.315 3.965 23.545 3.995 ;
        RECT 31.455 3.965 31.685 3.995 ;
        RECT 36.265 3.965 36.495 3.995 ;
        RECT 40.335 3.965 40.565 3.995 ;
        RECT 47.735 3.965 47.965 3.995 ;
        RECT 55.875 3.965 56.105 3.995 ;
        RECT 60.685 3.965 60.915 3.995 ;
        RECT 64.755 3.965 64.985 3.995 ;
        RECT 72.155 3.965 72.385 3.995 ;
        RECT 7.005 3.795 23.575 3.965 ;
        RECT 31.425 3.795 47.995 3.965 ;
        RECT 55.845 3.795 72.415 3.965 ;
        RECT 7.035 3.765 7.265 3.795 ;
        RECT 11.845 3.765 12.075 3.795 ;
        RECT 15.915 3.765 16.145 3.795 ;
        RECT 23.315 3.765 23.545 3.795 ;
        RECT 31.455 3.765 31.685 3.795 ;
        RECT 36.265 3.765 36.495 3.795 ;
        RECT 40.335 3.765 40.565 3.795 ;
        RECT 47.735 3.765 47.965 3.795 ;
        RECT 55.875 3.765 56.105 3.795 ;
        RECT 60.685 3.765 60.915 3.795 ;
        RECT 64.755 3.765 64.985 3.795 ;
        RECT 72.155 3.765 72.385 3.795 ;
        RECT 18.505 3.595 18.735 3.625 ;
        RECT 24.055 3.595 24.285 3.625 ;
        RECT 79.555 3.595 79.785 3.625 ;
        RECT 18.475 3.425 79.815 3.595 ;
        RECT 18.505 3.395 18.735 3.425 ;
        RECT 24.055 3.395 24.285 3.425 ;
        RECT 79.555 3.395 79.785 3.425 ;
        RECT 75.485 3.225 75.715 3.255 ;
        RECT 51.095 3.055 75.745 3.225 ;
        RECT 2.965 2.855 3.195 2.885 ;
        RECT 4.815 2.855 5.045 2.880 ;
        RECT 9.625 2.855 9.855 2.885 ;
        RECT 12.585 2.855 12.815 2.885 ;
        RECT 14.435 2.855 14.665 2.885 ;
        RECT 27.385 2.855 27.615 2.885 ;
        RECT 29.235 2.855 29.465 2.880 ;
        RECT 34.045 2.855 34.275 2.885 ;
        RECT 37.005 2.855 37.235 2.885 ;
        RECT 38.855 2.855 39.085 2.885 ;
        RECT 43.665 2.855 43.895 2.885 ;
        RECT 45.515 2.855 45.745 2.885 ;
        RECT 48.475 2.855 48.705 2.885 ;
        RECT 51.095 2.855 51.265 3.055 ;
        RECT 75.485 3.025 75.715 3.055 ;
        RECT 51.805 2.855 52.035 2.885 ;
        RECT 53.655 2.855 53.885 2.880 ;
        RECT 58.465 2.855 58.695 2.885 ;
        RECT 61.425 2.855 61.655 2.885 ;
        RECT 63.275 2.855 63.505 2.885 ;
        RECT 2.935 2.685 9.885 2.855 ;
        RECT 12.555 2.685 14.695 2.855 ;
        RECT 27.355 2.685 34.305 2.855 ;
        RECT 36.975 2.685 39.115 2.855 ;
        RECT 43.635 2.685 45.775 2.855 ;
        RECT 48.445 2.685 51.265 2.855 ;
        RECT 51.775 2.685 58.725 2.855 ;
        RECT 61.395 2.685 63.535 2.855 ;
        RECT 2.965 2.655 3.195 2.685 ;
        RECT 4.785 2.680 5.195 2.685 ;
        RECT 4.815 2.650 5.045 2.680 ;
        RECT 9.625 2.655 9.855 2.685 ;
        RECT 12.585 2.655 12.815 2.685 ;
        RECT 14.435 2.655 14.665 2.685 ;
        RECT 27.385 2.655 27.615 2.685 ;
        RECT 29.205 2.680 29.615 2.685 ;
        RECT 29.235 2.650 29.465 2.680 ;
        RECT 34.045 2.655 34.275 2.685 ;
        RECT 37.005 2.655 37.235 2.685 ;
        RECT 38.855 2.655 39.085 2.685 ;
        RECT 43.665 2.655 43.895 2.685 ;
        RECT 45.515 2.655 45.745 2.685 ;
        RECT 48.475 2.655 48.705 2.685 ;
        RECT 51.805 2.655 52.035 2.685 ;
        RECT 53.625 2.680 54.035 2.685 ;
        RECT 53.655 2.650 53.885 2.680 ;
        RECT 58.465 2.655 58.695 2.685 ;
        RECT 61.425 2.655 61.655 2.685 ;
        RECT 63.275 2.655 63.505 2.685 ;
        RECT 79.555 2.345 79.785 2.375 ;
        RECT 81.035 2.345 81.265 2.375 ;
        RECT 79.525 2.175 81.295 2.345 ;
        RECT 79.555 2.145 79.785 2.175 ;
        RECT 81.035 2.145 81.265 2.175 ;
        RECT 75.785 1.445 76.015 1.475 ;
        RECT 79.115 1.445 79.345 1.475 ;
        RECT 82.445 1.445 82.675 1.475 ;
        RECT 75.755 1.275 82.705 1.445 ;
        RECT 75.785 1.245 76.015 1.275 ;
        RECT 79.115 1.245 79.345 1.275 ;
        RECT 82.445 1.245 82.675 1.275 ;
  END
END TMRDFFSNQX1
END LIBRARY

